VERSION 5.7 ;
  NOWIREEXTENSIONATPIN ON ;
  DIVIDERCHAR "/" ;
  BUSBITCHARS "[]" ;
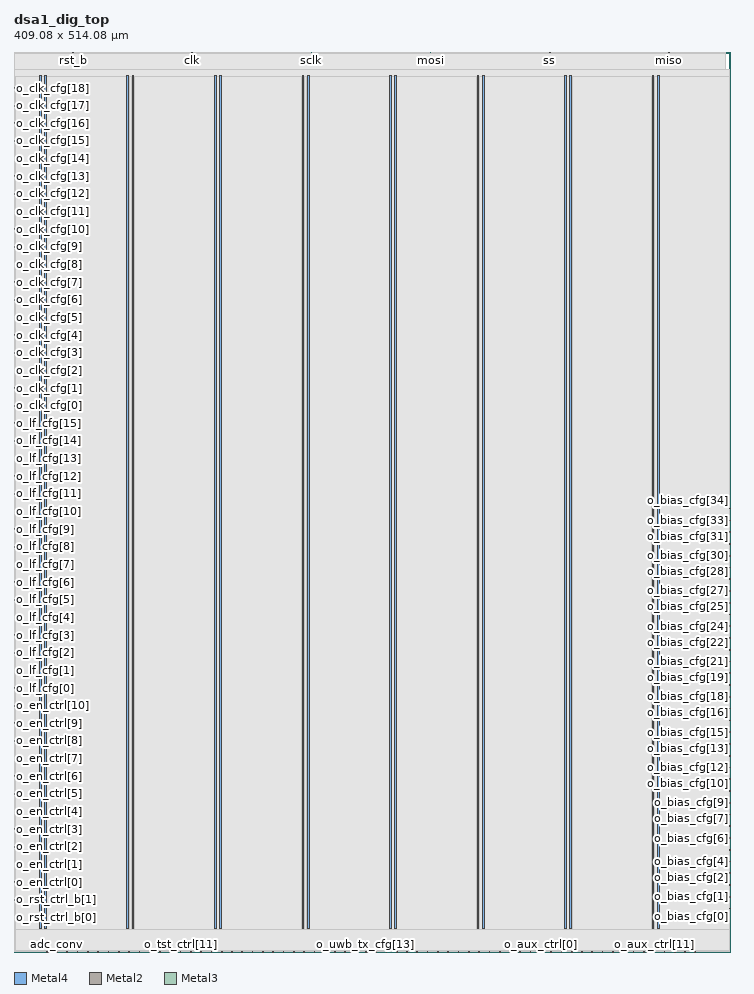
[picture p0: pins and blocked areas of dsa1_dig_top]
MACRO dsa1_dig_top
  CLASS BLOCK ;
  FOREIGN dsa1_dig_top ;
  ORIGIN 0.000 0.000 ;
  SIZE 409.080 BY 514.080 ;
  PIN VDD
    DIRECTION INOUT ;
    USE POWER ;
    PORT
      LAYER Metal4 ;
        RECT 14.540 13.280 15.540 500.800 ;
    END
    PORT
      LAYER Metal4 ;
        RECT 64.540 13.280 65.540 500.800 ;
    END
    PORT
      LAYER Metal4 ;
        RECT 114.540 13.280 115.540 500.800 ;
    END
    PORT
      LAYER Metal4 ;
        RECT 164.540 13.280 165.540 500.800 ;
    END
    PORT
      LAYER Metal4 ;
        RECT 214.540 13.280 215.540 500.800 ;
    END
    PORT
      LAYER Metal4 ;
        RECT 264.540 13.280 265.540 500.800 ;
    END
    PORT
      LAYER Metal4 ;
        RECT 314.540 13.280 315.540 500.800 ;
    END
    PORT
      LAYER Metal4 ;
        RECT 364.540 13.280 365.540 500.800 ;
    END
  END VDD
  PIN VSS
    DIRECTION INOUT ;
    USE GROUND ;
    PORT
      LAYER Metal4 ;
        RECT 17.540 13.280 18.540 500.800 ;
    END
    PORT
      LAYER Metal4 ;
        RECT 67.540 13.280 68.540 500.800 ;
    END
    PORT
      LAYER Metal4 ;
        RECT 117.540 13.280 118.540 500.800 ;
    END
    PORT
      LAYER Metal4 ;
        RECT 167.540 13.280 168.540 500.800 ;
    END
    PORT
      LAYER Metal4 ;
        RECT 217.540 13.280 218.540 500.800 ;
    END
    PORT
      LAYER Metal4 ;
        RECT 267.540 13.280 268.540 500.800 ;
    END
    PORT
      LAYER Metal4 ;
        RECT 317.540 13.280 318.540 500.800 ;
    END
    PORT
      LAYER Metal4 ;
        RECT 367.540 13.280 368.540 500.800 ;
    END
  END VSS
  PIN adc_conv
    DIRECTION OUTPUT ;
    USE SIGNAL ;
    ANTENNADIFFAREA 0.741200 ;
    PORT
      LAYER Metal2 ;
        RECT 24.370 0.000 24.770 0.400 ;
    END
  END adc_conv
  PIN clk
    DIRECTION INPUT ;
    USE SIGNAL ;
    ANTENNAGATEAREA 0.566800 ;
    PORT
      LAYER Metal2 ;
        RECT 101.650 513.680 102.050 514.080 ;
    END
  END clk
  PIN data_in
    DIRECTION INPUT ;
    USE SIGNAL ;
    ANTENNAGATEAREA 0.101400 ;
    PORT
      LAYER Metal2 ;
        RECT 18.490 0.000 18.890 0.400 ;
    END
  END data_in
  PIN miso
    DIRECTION OUTPUT ;
    USE SIGNAL ;
    ANTENNADIFFAREA 0.741200 ;
    PORT
      LAYER Metal2 ;
        RECT 373.810 513.680 374.210 514.080 ;
    END
  END miso
  PIN mosi
    DIRECTION INPUT ;
    USE SIGNAL ;
    ANTENNAGATEAREA 0.101400 ;
    PORT
      LAYER Metal2 ;
        RECT 237.730 513.680 238.130 514.080 ;
    END
  END mosi
  PIN o_aux_ctrl[0]
    DIRECTION OUTPUT ;
    USE SIGNAL ;
    ANTENNADIFFAREA 0.741200 ;
    PORT
      LAYER Metal2 ;
        RECT 300.730 0.000 301.130 0.400 ;
    END
  END o_aux_ctrl[0]
  PIN o_aux_ctrl[10]
    DIRECTION OUTPUT ;
    USE SIGNAL ;
    ANTENNADIFFAREA 0.741200 ;
    PORT
      LAYER Metal2 ;
        RECT 359.530 0.000 359.930 0.400 ;
    END
  END o_aux_ctrl[10]
  PIN o_aux_ctrl[11]
    DIRECTION OUTPUT ;
    USE SIGNAL ;
    ANTENNADIFFAREA 0.741200 ;
    PORT
      LAYER Metal2 ;
        RECT 365.410 0.000 365.810 0.400 ;
    END
  END o_aux_ctrl[11]
  PIN o_aux_ctrl[12]
    DIRECTION OUTPUT ;
    USE SIGNAL ;
    ANTENNADIFFAREA 0.741200 ;
    PORT
      LAYER Metal2 ;
        RECT 371.290 0.000 371.690 0.400 ;
    END
  END o_aux_ctrl[12]
  PIN o_aux_ctrl[13]
    DIRECTION OUTPUT ;
    USE SIGNAL ;
    ANTENNADIFFAREA 0.741200 ;
    PORT
      LAYER Metal2 ;
        RECT 377.170 0.000 377.570 0.400 ;
    END
  END o_aux_ctrl[13]
  PIN o_aux_ctrl[14]
    DIRECTION OUTPUT ;
    USE SIGNAL ;
    ANTENNADIFFAREA 0.741200 ;
    PORT
      LAYER Metal2 ;
        RECT 383.050 0.000 383.450 0.400 ;
    END
  END o_aux_ctrl[14]
  PIN o_aux_ctrl[15]
    DIRECTION OUTPUT ;
    USE SIGNAL ;
    ANTENNADIFFAREA 0.741200 ;
    PORT
      LAYER Metal2 ;
        RECT 388.930 0.000 389.330 0.400 ;
    END
  END o_aux_ctrl[15]
  PIN o_aux_ctrl[1]
    DIRECTION OUTPUT ;
    USE SIGNAL ;
    ANTENNADIFFAREA 0.741200 ;
    PORT
      LAYER Metal2 ;
        RECT 306.610 0.000 307.010 0.400 ;
    END
  END o_aux_ctrl[1]
  PIN o_aux_ctrl[2]
    DIRECTION OUTPUT ;
    USE SIGNAL ;
    ANTENNADIFFAREA 0.741200 ;
    PORT
      LAYER Metal2 ;
        RECT 312.490 0.000 312.890 0.400 ;
    END
  END o_aux_ctrl[2]
  PIN o_aux_ctrl[3]
    DIRECTION OUTPUT ;
    USE SIGNAL ;
    ANTENNADIFFAREA 0.741200 ;
    PORT
      LAYER Metal2 ;
        RECT 318.370 0.000 318.770 0.400 ;
    END
  END o_aux_ctrl[3]
  PIN o_aux_ctrl[4]
    DIRECTION OUTPUT ;
    USE SIGNAL ;
    ANTENNADIFFAREA 0.741200 ;
    PORT
      LAYER Metal2 ;
        RECT 324.250 0.000 324.650 0.400 ;
    END
  END o_aux_ctrl[4]
  PIN o_aux_ctrl[5]
    DIRECTION OUTPUT ;
    USE SIGNAL ;
    ANTENNADIFFAREA 0.741200 ;
    PORT
      LAYER Metal2 ;
        RECT 330.130 0.000 330.530 0.400 ;
    END
  END o_aux_ctrl[5]
  PIN o_aux_ctrl[6]
    DIRECTION OUTPUT ;
    USE SIGNAL ;
    ANTENNADIFFAREA 0.741200 ;
    PORT
      LAYER Metal2 ;
        RECT 336.010 0.000 336.410 0.400 ;
    END
  END o_aux_ctrl[6]
  PIN o_aux_ctrl[7]
    DIRECTION OUTPUT ;
    USE SIGNAL ;
    ANTENNADIFFAREA 0.741200 ;
    PORT
      LAYER Metal2 ;
        RECT 341.890 0.000 342.290 0.400 ;
    END
  END o_aux_ctrl[7]
  PIN o_aux_ctrl[8]
    DIRECTION OUTPUT ;
    USE SIGNAL ;
    ANTENNADIFFAREA 0.741200 ;
    PORT
      LAYER Metal2 ;
        RECT 347.770 0.000 348.170 0.400 ;
    END
  END o_aux_ctrl[8]
  PIN o_aux_ctrl[9]
    DIRECTION OUTPUT ;
    USE SIGNAL ;
    ANTENNADIFFAREA 0.741200 ;
    PORT
      LAYER Metal2 ;
        RECT 353.650 0.000 354.050 0.400 ;
    END
  END o_aux_ctrl[9]
  PIN o_bias_cfg[0]
    DIRECTION OUTPUT ;
    USE SIGNAL ;
    ANTENNADIFFAREA 0.741200 ;
    PORT
      LAYER Metal3 ;
        RECT 408.680 24.580 409.080 24.980 ;
    END
  END o_bias_cfg[0]
  PIN o_bias_cfg[10]
    DIRECTION OUTPUT ;
    USE SIGNAL ;
    ANTENNADIFFAREA 0.741200 ;
    PORT
      LAYER Metal3 ;
        RECT 408.680 91.780 409.080 92.180 ;
    END
  END o_bias_cfg[10]
  PIN o_bias_cfg[11]
    DIRECTION OUTPUT ;
    USE SIGNAL ;
    ANTENNADIFFAREA 0.741200 ;
    PORT
      LAYER Metal3 ;
        RECT 408.680 98.500 409.080 98.900 ;
    END
  END o_bias_cfg[11]
  PIN o_bias_cfg[12]
    DIRECTION OUTPUT ;
    USE SIGNAL ;
    ANTENNADIFFAREA 0.741200 ;
    PORT
      LAYER Metal3 ;
        RECT 408.680 105.220 409.080 105.620 ;
    END
  END o_bias_cfg[12]
  PIN o_bias_cfg[13]
    DIRECTION OUTPUT ;
    USE SIGNAL ;
    ANTENNADIFFAREA 0.741200 ;
    PORT
      LAYER Metal3 ;
        RECT 408.680 111.940 409.080 112.340 ;
    END
  END o_bias_cfg[13]
  PIN o_bias_cfg[14]
    DIRECTION OUTPUT ;
    USE SIGNAL ;
    ANTENNADIFFAREA 0.741200 ;
    PORT
      LAYER Metal3 ;
        RECT 408.680 118.660 409.080 119.060 ;
    END
  END o_bias_cfg[14]
  PIN o_bias_cfg[15]
    DIRECTION OUTPUT ;
    USE SIGNAL ;
    ANTENNADIFFAREA 0.741200 ;
    PORT
      LAYER Metal3 ;
        RECT 408.680 125.380 409.080 125.780 ;
    END
  END o_bias_cfg[15]
  PIN o_bias_cfg[16]
    DIRECTION OUTPUT ;
    USE SIGNAL ;
    ANTENNADIFFAREA 0.741200 ;
    PORT
      LAYER Metal3 ;
        RECT 408.680 132.100 409.080 132.500 ;
    END
  END o_bias_cfg[16]
  PIN o_bias_cfg[17]
    DIRECTION OUTPUT ;
    USE SIGNAL ;
    ANTENNADIFFAREA 0.741200 ;
    PORT
      LAYER Metal3 ;
        RECT 408.680 138.820 409.080 139.220 ;
    END
  END o_bias_cfg[17]
  PIN o_bias_cfg[18]
    DIRECTION OUTPUT ;
    USE SIGNAL ;
    ANTENNADIFFAREA 0.741200 ;
    PORT
      LAYER Metal3 ;
        RECT 408.680 145.540 409.080 145.940 ;
    END
  END o_bias_cfg[18]
  PIN o_bias_cfg[19]
    DIRECTION OUTPUT ;
    USE SIGNAL ;
    ANTENNADIFFAREA 0.741200 ;
    PORT
      LAYER Metal3 ;
        RECT 408.680 152.260 409.080 152.660 ;
    END
  END o_bias_cfg[19]
  PIN o_bias_cfg[1]
    DIRECTION OUTPUT ;
    USE SIGNAL ;
    ANTENNADIFFAREA 0.741200 ;
    PORT
      LAYER Metal3 ;
        RECT 408.680 31.300 409.080 31.700 ;
    END
  END o_bias_cfg[1]
  PIN o_bias_cfg[20]
    DIRECTION OUTPUT ;
    USE SIGNAL ;
    ANTENNADIFFAREA 0.741200 ;
    PORT
      LAYER Metal3 ;
        RECT 408.680 158.980 409.080 159.380 ;
    END
  END o_bias_cfg[20]
  PIN o_bias_cfg[21]
    DIRECTION OUTPUT ;
    USE SIGNAL ;
    ANTENNADIFFAREA 0.741200 ;
    PORT
      LAYER Metal3 ;
        RECT 408.680 165.700 409.080 166.100 ;
    END
  END o_bias_cfg[21]
  PIN o_bias_cfg[22]
    DIRECTION OUTPUT ;
    USE SIGNAL ;
    ANTENNADIFFAREA 0.741200 ;
    PORT
      LAYER Metal3 ;
        RECT 408.680 172.420 409.080 172.820 ;
    END
  END o_bias_cfg[22]
  PIN o_bias_cfg[23]
    DIRECTION OUTPUT ;
    USE SIGNAL ;
    ANTENNADIFFAREA 0.741200 ;
    PORT
      LAYER Metal3 ;
        RECT 408.680 179.140 409.080 179.540 ;
    END
  END o_bias_cfg[23]
  PIN o_bias_cfg[24]
    DIRECTION OUTPUT ;
    USE SIGNAL ;
    ANTENNADIFFAREA 0.741200 ;
    PORT
      LAYER Metal3 ;
        RECT 408.680 185.860 409.080 186.260 ;
    END
  END o_bias_cfg[24]
  PIN o_bias_cfg[25]
    DIRECTION OUTPUT ;
    USE SIGNAL ;
    ANTENNADIFFAREA 0.741200 ;
    PORT
      LAYER Metal3 ;
        RECT 408.680 192.580 409.080 192.980 ;
    END
  END o_bias_cfg[25]
  PIN o_bias_cfg[26]
    DIRECTION OUTPUT ;
    USE SIGNAL ;
    ANTENNADIFFAREA 0.741200 ;
    PORT
      LAYER Metal3 ;
        RECT 408.680 199.300 409.080 199.700 ;
    END
  END o_bias_cfg[26]
  PIN o_bias_cfg[27]
    DIRECTION OUTPUT ;
    USE SIGNAL ;
    ANTENNADIFFAREA 0.741200 ;
    PORT
      LAYER Metal3 ;
        RECT 408.680 206.020 409.080 206.420 ;
    END
  END o_bias_cfg[27]
  PIN o_bias_cfg[28]
    DIRECTION OUTPUT ;
    USE SIGNAL ;
    ANTENNADIFFAREA 0.741200 ;
    PORT
      LAYER Metal3 ;
        RECT 408.680 212.740 409.080 213.140 ;
    END
  END o_bias_cfg[28]
  PIN o_bias_cfg[29]
    DIRECTION OUTPUT ;
    USE SIGNAL ;
    ANTENNADIFFAREA 0.741200 ;
    PORT
      LAYER Metal3 ;
        RECT 408.680 219.460 409.080 219.860 ;
    END
  END o_bias_cfg[29]
  PIN o_bias_cfg[2]
    DIRECTION OUTPUT ;
    USE SIGNAL ;
    ANTENNADIFFAREA 0.741200 ;
    PORT
      LAYER Metal3 ;
        RECT 408.680 38.020 409.080 38.420 ;
    END
  END o_bias_cfg[2]
  PIN o_bias_cfg[30]
    DIRECTION OUTPUT ;
    USE SIGNAL ;
    ANTENNADIFFAREA 0.741200 ;
    PORT
      LAYER Metal3 ;
        RECT 408.680 226.180 409.080 226.580 ;
    END
  END o_bias_cfg[30]
  PIN o_bias_cfg[31]
    DIRECTION OUTPUT ;
    USE SIGNAL ;
    ANTENNADIFFAREA 0.741200 ;
    PORT
      LAYER Metal3 ;
        RECT 408.680 232.900 409.080 233.300 ;
    END
  END o_bias_cfg[31]
  PIN o_bias_cfg[32]
    DIRECTION OUTPUT ;
    USE SIGNAL ;
    ANTENNADIFFAREA 0.741200 ;
    PORT
      LAYER Metal3 ;
        RECT 408.680 239.620 409.080 240.020 ;
    END
  END o_bias_cfg[32]
  PIN o_bias_cfg[33]
    DIRECTION OUTPUT ;
    USE SIGNAL ;
    ANTENNADIFFAREA 0.741200 ;
    PORT
      LAYER Metal3 ;
        RECT 408.680 246.340 409.080 246.740 ;
    END
  END o_bias_cfg[33]
  PIN o_bias_cfg[34]
    DIRECTION OUTPUT ;
    USE SIGNAL ;
    ANTENNADIFFAREA 0.741200 ;
    PORT
      LAYER Metal3 ;
        RECT 408.680 253.060 409.080 253.460 ;
    END
  END o_bias_cfg[34]
  PIN o_bias_cfg[3]
    DIRECTION OUTPUT ;
    USE SIGNAL ;
    ANTENNADIFFAREA 0.741200 ;
    PORT
      LAYER Metal3 ;
        RECT 408.680 44.740 409.080 45.140 ;
    END
  END o_bias_cfg[3]
  PIN o_bias_cfg[4]
    DIRECTION OUTPUT ;
    USE SIGNAL ;
    ANTENNADIFFAREA 0.741200 ;
    PORT
      LAYER Metal3 ;
        RECT 408.680 51.460 409.080 51.860 ;
    END
  END o_bias_cfg[4]
  PIN o_bias_cfg[5]
    DIRECTION OUTPUT ;
    USE SIGNAL ;
    ANTENNADIFFAREA 0.741200 ;
    PORT
      LAYER Metal3 ;
        RECT 408.680 58.180 409.080 58.580 ;
    END
  END o_bias_cfg[5]
  PIN o_bias_cfg[6]
    DIRECTION OUTPUT ;
    USE SIGNAL ;
    ANTENNADIFFAREA 0.741200 ;
    PORT
      LAYER Metal3 ;
        RECT 408.680 64.900 409.080 65.300 ;
    END
  END o_bias_cfg[6]
  PIN o_bias_cfg[7]
    DIRECTION OUTPUT ;
    USE SIGNAL ;
    ANTENNADIFFAREA 0.741200 ;
    PORT
      LAYER Metal3 ;
        RECT 408.680 71.620 409.080 72.020 ;
    END
  END o_bias_cfg[7]
  PIN o_bias_cfg[8]
    DIRECTION OUTPUT ;
    USE SIGNAL ;
    ANTENNADIFFAREA 0.741200 ;
    PORT
      LAYER Metal3 ;
        RECT 408.680 78.340 409.080 78.740 ;
    END
  END o_bias_cfg[8]
  PIN o_bias_cfg[9]
    DIRECTION OUTPUT ;
    USE SIGNAL ;
    ANTENNADIFFAREA 0.741200 ;
    PORT
      LAYER Metal3 ;
        RECT 408.680 85.060 409.080 85.460 ;
    END
  END o_bias_cfg[9]
  PIN o_clk_cfg[0]
    DIRECTION OUTPUT ;
    USE SIGNAL ;
    ANTENNADIFFAREA 0.741200 ;
    PORT
      LAYER Metal3 ;
        RECT 0.000 311.860 0.400 312.260 ;
    END
  END o_clk_cfg[0]
  PIN o_clk_cfg[10]
    DIRECTION OUTPUT ;
    USE SIGNAL ;
    ANTENNADIFFAREA 0.741200 ;
    PORT
      LAYER Metal3 ;
        RECT 0.000 412.660 0.400 413.060 ;
    END
  END o_clk_cfg[10]
  PIN o_clk_cfg[11]
    DIRECTION OUTPUT ;
    USE SIGNAL ;
    ANTENNADIFFAREA 0.741200 ;
    PORT
      LAYER Metal3 ;
        RECT 0.000 422.740 0.400 423.140 ;
    END
  END o_clk_cfg[11]
  PIN o_clk_cfg[12]
    DIRECTION OUTPUT ;
    USE SIGNAL ;
    ANTENNADIFFAREA 0.741200 ;
    PORT
      LAYER Metal3 ;
        RECT 0.000 432.820 0.400 433.220 ;
    END
  END o_clk_cfg[12]
  PIN o_clk_cfg[13]
    DIRECTION OUTPUT ;
    USE SIGNAL ;
    ANTENNADIFFAREA 0.741200 ;
    PORT
      LAYER Metal3 ;
        RECT 0.000 442.900 0.400 443.300 ;
    END
  END o_clk_cfg[13]
  PIN o_clk_cfg[14]
    DIRECTION OUTPUT ;
    USE SIGNAL ;
    ANTENNADIFFAREA 0.741200 ;
    PORT
      LAYER Metal3 ;
        RECT 0.000 452.980 0.400 453.380 ;
    END
  END o_clk_cfg[14]
  PIN o_clk_cfg[15]
    DIRECTION OUTPUT ;
    USE SIGNAL ;
    ANTENNADIFFAREA 0.741200 ;
    PORT
      LAYER Metal3 ;
        RECT 0.000 463.060 0.400 463.460 ;
    END
  END o_clk_cfg[15]
  PIN o_clk_cfg[16]
    DIRECTION OUTPUT ;
    USE SIGNAL ;
    ANTENNADIFFAREA 0.741200 ;
    PORT
      LAYER Metal3 ;
        RECT 0.000 473.140 0.400 473.540 ;
    END
  END o_clk_cfg[16]
  PIN o_clk_cfg[17]
    DIRECTION OUTPUT ;
    USE SIGNAL ;
    ANTENNADIFFAREA 0.741200 ;
    PORT
      LAYER Metal3 ;
        RECT 0.000 483.220 0.400 483.620 ;
    END
  END o_clk_cfg[17]
  PIN o_clk_cfg[18]
    DIRECTION OUTPUT ;
    USE SIGNAL ;
    ANTENNADIFFAREA 0.741200 ;
    PORT
      LAYER Metal3 ;
        RECT 0.000 493.300 0.400 493.700 ;
    END
  END o_clk_cfg[18]
  PIN o_clk_cfg[1]
    DIRECTION OUTPUT ;
    USE SIGNAL ;
    ANTENNADIFFAREA 0.741200 ;
    PORT
      LAYER Metal3 ;
        RECT 0.000 321.940 0.400 322.340 ;
    END
  END o_clk_cfg[1]
  PIN o_clk_cfg[2]
    DIRECTION OUTPUT ;
    USE SIGNAL ;
    ANTENNADIFFAREA 0.741200 ;
    PORT
      LAYER Metal3 ;
        RECT 0.000 332.020 0.400 332.420 ;
    END
  END o_clk_cfg[2]
  PIN o_clk_cfg[3]
    DIRECTION OUTPUT ;
    USE SIGNAL ;
    ANTENNADIFFAREA 0.741200 ;
    PORT
      LAYER Metal3 ;
        RECT 0.000 342.100 0.400 342.500 ;
    END
  END o_clk_cfg[3]
  PIN o_clk_cfg[4]
    DIRECTION OUTPUT ;
    USE SIGNAL ;
    ANTENNADIFFAREA 0.741200 ;
    PORT
      LAYER Metal3 ;
        RECT 0.000 352.180 0.400 352.580 ;
    END
  END o_clk_cfg[4]
  PIN o_clk_cfg[5]
    DIRECTION OUTPUT ;
    USE SIGNAL ;
    ANTENNADIFFAREA 0.741200 ;
    PORT
      LAYER Metal3 ;
        RECT 0.000 362.260 0.400 362.660 ;
    END
  END o_clk_cfg[5]
  PIN o_clk_cfg[6]
    DIRECTION OUTPUT ;
    USE SIGNAL ;
    ANTENNADIFFAREA 0.741200 ;
    PORT
      LAYER Metal3 ;
        RECT 0.000 372.340 0.400 372.740 ;
    END
  END o_clk_cfg[6]
  PIN o_clk_cfg[7]
    DIRECTION OUTPUT ;
    USE SIGNAL ;
    ANTENNADIFFAREA 0.741200 ;
    PORT
      LAYER Metal3 ;
        RECT 0.000 382.420 0.400 382.820 ;
    END
  END o_clk_cfg[7]
  PIN o_clk_cfg[8]
    DIRECTION OUTPUT ;
    USE SIGNAL ;
    ANTENNADIFFAREA 0.741200 ;
    PORT
      LAYER Metal3 ;
        RECT 0.000 392.500 0.400 392.900 ;
    END
  END o_clk_cfg[8]
  PIN o_clk_cfg[9]
    DIRECTION OUTPUT ;
    USE SIGNAL ;
    ANTENNADIFFAREA 0.741200 ;
    PORT
      LAYER Metal3 ;
        RECT 0.000 402.580 0.400 402.980 ;
    END
  END o_clk_cfg[9]
  PIN o_en_ctrl[0]
    DIRECTION OUTPUT ;
    USE SIGNAL ;
    ANTENNADIFFAREA 0.741200 ;
    PORT
      LAYER Metal3 ;
        RECT 0.000 39.700 0.400 40.100 ;
    END
  END o_en_ctrl[0]
  PIN o_en_ctrl[10]
    DIRECTION OUTPUT ;
    USE SIGNAL ;
    ANTENNADIFFAREA 0.741200 ;
    PORT
      LAYER Metal3 ;
        RECT 0.000 140.500 0.400 140.900 ;
    END
  END o_en_ctrl[10]
  PIN o_en_ctrl[1]
    DIRECTION OUTPUT ;
    USE SIGNAL ;
    ANTENNADIFFAREA 0.741200 ;
    PORT
      LAYER Metal3 ;
        RECT 0.000 49.780 0.400 50.180 ;
    END
  END o_en_ctrl[1]
  PIN o_en_ctrl[2]
    DIRECTION OUTPUT ;
    USE SIGNAL ;
    ANTENNADIFFAREA 0.741200 ;
    PORT
      LAYER Metal3 ;
        RECT 0.000 59.860 0.400 60.260 ;
    END
  END o_en_ctrl[2]
  PIN o_en_ctrl[3]
    DIRECTION OUTPUT ;
    USE SIGNAL ;
    ANTENNADIFFAREA 0.741200 ;
    PORT
      LAYER Metal3 ;
        RECT 0.000 69.940 0.400 70.340 ;
    END
  END o_en_ctrl[3]
  PIN o_en_ctrl[4]
    DIRECTION OUTPUT ;
    USE SIGNAL ;
    ANTENNADIFFAREA 0.741200 ;
    PORT
      LAYER Metal3 ;
        RECT 0.000 80.020 0.400 80.420 ;
    END
  END o_en_ctrl[4]
  PIN o_en_ctrl[5]
    DIRECTION OUTPUT ;
    USE SIGNAL ;
    ANTENNADIFFAREA 0.741200 ;
    PORT
      LAYER Metal3 ;
        RECT 0.000 90.100 0.400 90.500 ;
    END
  END o_en_ctrl[5]
  PIN o_en_ctrl[6]
    DIRECTION OUTPUT ;
    USE SIGNAL ;
    ANTENNADIFFAREA 0.741200 ;
    PORT
      LAYER Metal3 ;
        RECT 0.000 100.180 0.400 100.580 ;
    END
  END o_en_ctrl[6]
  PIN o_en_ctrl[7]
    DIRECTION OUTPUT ;
    USE SIGNAL ;
    ANTENNADIFFAREA 0.741200 ;
    PORT
      LAYER Metal3 ;
        RECT 0.000 110.260 0.400 110.660 ;
    END
  END o_en_ctrl[7]
  PIN o_en_ctrl[8]
    DIRECTION OUTPUT ;
    USE SIGNAL ;
    ANTENNADIFFAREA 0.741200 ;
    PORT
      LAYER Metal3 ;
        RECT 0.000 120.340 0.400 120.740 ;
    END
  END o_en_ctrl[8]
  PIN o_en_ctrl[9]
    DIRECTION OUTPUT ;
    USE SIGNAL ;
    ANTENNADIFFAREA 0.741200 ;
    PORT
      LAYER Metal3 ;
        RECT 0.000 130.420 0.400 130.820 ;
    END
  END o_en_ctrl[9]
  PIN o_lf_cfg[0]
    DIRECTION OUTPUT ;
    USE SIGNAL ;
    ANTENNADIFFAREA 0.741200 ;
    PORT
      LAYER Metal3 ;
        RECT 0.000 150.580 0.400 150.980 ;
    END
  END o_lf_cfg[0]
  PIN o_lf_cfg[10]
    DIRECTION OUTPUT ;
    USE SIGNAL ;
    ANTENNADIFFAREA 0.741200 ;
    PORT
      LAYER Metal3 ;
        RECT 0.000 251.380 0.400 251.780 ;
    END
  END o_lf_cfg[10]
  PIN o_lf_cfg[11]
    DIRECTION OUTPUT ;
    USE SIGNAL ;
    ANTENNADIFFAREA 0.741200 ;
    PORT
      LAYER Metal3 ;
        RECT 0.000 261.460 0.400 261.860 ;
    END
  END o_lf_cfg[11]
  PIN o_lf_cfg[12]
    DIRECTION OUTPUT ;
    USE SIGNAL ;
    ANTENNADIFFAREA 0.741200 ;
    PORT
      LAYER Metal3 ;
        RECT 0.000 271.540 0.400 271.940 ;
    END
  END o_lf_cfg[12]
  PIN o_lf_cfg[13]
    DIRECTION OUTPUT ;
    USE SIGNAL ;
    ANTENNADIFFAREA 0.741200 ;
    PORT
      LAYER Metal3 ;
        RECT 0.000 281.620 0.400 282.020 ;
    END
  END o_lf_cfg[13]
  PIN o_lf_cfg[14]
    DIRECTION OUTPUT ;
    USE SIGNAL ;
    ANTENNADIFFAREA 0.741200 ;
    PORT
      LAYER Metal3 ;
        RECT 0.000 291.700 0.400 292.100 ;
    END
  END o_lf_cfg[14]
  PIN o_lf_cfg[15]
    DIRECTION OUTPUT ;
    USE SIGNAL ;
    ANTENNADIFFAREA 0.741200 ;
    PORT
      LAYER Metal3 ;
        RECT 0.000 301.780 0.400 302.180 ;
    END
  END o_lf_cfg[15]
  PIN o_lf_cfg[1]
    DIRECTION OUTPUT ;
    USE SIGNAL ;
    ANTENNADIFFAREA 0.741200 ;
    PORT
      LAYER Metal3 ;
        RECT 0.000 160.660 0.400 161.060 ;
    END
  END o_lf_cfg[1]
  PIN o_lf_cfg[2]
    DIRECTION OUTPUT ;
    USE SIGNAL ;
    ANTENNADIFFAREA 0.741200 ;
    PORT
      LAYER Metal3 ;
        RECT 0.000 170.740 0.400 171.140 ;
    END
  END o_lf_cfg[2]
  PIN o_lf_cfg[3]
    DIRECTION OUTPUT ;
    USE SIGNAL ;
    ANTENNADIFFAREA 0.741200 ;
    PORT
      LAYER Metal3 ;
        RECT 0.000 180.820 0.400 181.220 ;
    END
  END o_lf_cfg[3]
  PIN o_lf_cfg[4]
    DIRECTION OUTPUT ;
    USE SIGNAL ;
    ANTENNADIFFAREA 0.741200 ;
    PORT
      LAYER Metal3 ;
        RECT 0.000 190.900 0.400 191.300 ;
    END
  END o_lf_cfg[4]
  PIN o_lf_cfg[5]
    DIRECTION OUTPUT ;
    USE SIGNAL ;
    ANTENNADIFFAREA 0.741200 ;
    PORT
      LAYER Metal3 ;
        RECT 0.000 200.980 0.400 201.380 ;
    END
  END o_lf_cfg[5]
  PIN o_lf_cfg[6]
    DIRECTION OUTPUT ;
    USE SIGNAL ;
    ANTENNADIFFAREA 0.741200 ;
    PORT
      LAYER Metal3 ;
        RECT 0.000 211.060 0.400 211.460 ;
    END
  END o_lf_cfg[6]
  PIN o_lf_cfg[7]
    DIRECTION OUTPUT ;
    USE SIGNAL ;
    ANTENNADIFFAREA 0.741200 ;
    PORT
      LAYER Metal3 ;
        RECT 0.000 221.140 0.400 221.540 ;
    END
  END o_lf_cfg[7]
  PIN o_lf_cfg[8]
    DIRECTION OUTPUT ;
    USE SIGNAL ;
    ANTENNADIFFAREA 0.741200 ;
    PORT
      LAYER Metal3 ;
        RECT 0.000 231.220 0.400 231.620 ;
    END
  END o_lf_cfg[8]
  PIN o_lf_cfg[9]
    DIRECTION OUTPUT ;
    USE SIGNAL ;
    ANTENNADIFFAREA 0.741200 ;
    PORT
      LAYER Metal3 ;
        RECT 0.000 241.300 0.400 241.700 ;
    END
  END o_lf_cfg[9]
  PIN o_rst_ctrl_b[0]
    DIRECTION OUTPUT ;
    USE SIGNAL ;
    ANTENNADIFFAREA 0.741200 ;
    PORT
      LAYER Metal3 ;
        RECT 0.000 19.540 0.400 19.940 ;
    END
  END o_rst_ctrl_b[0]
  PIN o_rst_ctrl_b[1]
    DIRECTION OUTPUT ;
    USE SIGNAL ;
    ANTENNADIFFAREA 0.741200 ;
    PORT
      LAYER Metal3 ;
        RECT 0.000 29.620 0.400 30.020 ;
    END
  END o_rst_ctrl_b[1]
  PIN o_tst_ctrl[0]
    DIRECTION OUTPUT ;
    USE SIGNAL ;
    ANTENNADIFFAREA 0.741200 ;
    PORT
      LAYER Metal2 ;
        RECT 30.250 0.000 30.650 0.400 ;
    END
  END o_tst_ctrl[0]
  PIN o_tst_ctrl[10]
    DIRECTION OUTPUT ;
    USE SIGNAL ;
    ANTENNADIFFAREA 0.741200 ;
    PORT
      LAYER Metal2 ;
        RECT 89.050 0.000 89.450 0.400 ;
    END
  END o_tst_ctrl[10]
  PIN o_tst_ctrl[11]
    DIRECTION OUTPUT ;
    USE SIGNAL ;
    ANTENNADIFFAREA 0.741200 ;
    PORT
      LAYER Metal2 ;
        RECT 94.930 0.000 95.330 0.400 ;
    END
  END o_tst_ctrl[11]
  PIN o_tst_ctrl[12]
    DIRECTION OUTPUT ;
    USE SIGNAL ;
    ANTENNADIFFAREA 0.741200 ;
    PORT
      LAYER Metal2 ;
        RECT 100.810 0.000 101.210 0.400 ;
    END
  END o_tst_ctrl[12]
  PIN o_tst_ctrl[13]
    DIRECTION OUTPUT ;
    USE SIGNAL ;
    ANTENNADIFFAREA 0.741200 ;
    PORT
      LAYER Metal2 ;
        RECT 106.690 0.000 107.090 0.400 ;
    END
  END o_tst_ctrl[13]
  PIN o_tst_ctrl[14]
    DIRECTION OUTPUT ;
    USE SIGNAL ;
    ANTENNADIFFAREA 0.741200 ;
    PORT
      LAYER Metal2 ;
        RECT 112.570 0.000 112.970 0.400 ;
    END
  END o_tst_ctrl[14]
  PIN o_tst_ctrl[15]
    DIRECTION OUTPUT ;
    USE SIGNAL ;
    ANTENNADIFFAREA 0.741200 ;
    PORT
      LAYER Metal2 ;
        RECT 118.450 0.000 118.850 0.400 ;
    END
  END o_tst_ctrl[15]
  PIN o_tst_ctrl[1]
    DIRECTION OUTPUT ;
    USE SIGNAL ;
    ANTENNADIFFAREA 0.741200 ;
    PORT
      LAYER Metal2 ;
        RECT 36.130 0.000 36.530 0.400 ;
    END
  END o_tst_ctrl[1]
  PIN o_tst_ctrl[2]
    DIRECTION OUTPUT ;
    USE SIGNAL ;
    ANTENNADIFFAREA 0.741200 ;
    PORT
      LAYER Metal2 ;
        RECT 42.010 0.000 42.410 0.400 ;
    END
  END o_tst_ctrl[2]
  PIN o_tst_ctrl[3]
    DIRECTION OUTPUT ;
    USE SIGNAL ;
    ANTENNADIFFAREA 0.741200 ;
    PORT
      LAYER Metal2 ;
        RECT 47.890 0.000 48.290 0.400 ;
    END
  END o_tst_ctrl[3]
  PIN o_tst_ctrl[4]
    DIRECTION OUTPUT ;
    USE SIGNAL ;
    ANTENNADIFFAREA 0.741200 ;
    PORT
      LAYER Metal2 ;
        RECT 53.770 0.000 54.170 0.400 ;
    END
  END o_tst_ctrl[4]
  PIN o_tst_ctrl[5]
    DIRECTION OUTPUT ;
    USE SIGNAL ;
    ANTENNADIFFAREA 0.741200 ;
    PORT
      LAYER Metal2 ;
        RECT 59.650 0.000 60.050 0.400 ;
    END
  END o_tst_ctrl[5]
  PIN o_tst_ctrl[6]
    DIRECTION OUTPUT ;
    USE SIGNAL ;
    ANTENNADIFFAREA 0.741200 ;
    PORT
      LAYER Metal2 ;
        RECT 65.530 0.000 65.930 0.400 ;
    END
  END o_tst_ctrl[6]
  PIN o_tst_ctrl[7]
    DIRECTION OUTPUT ;
    USE SIGNAL ;
    ANTENNADIFFAREA 0.741200 ;
    PORT
      LAYER Metal2 ;
        RECT 71.410 0.000 71.810 0.400 ;
    END
  END o_tst_ctrl[7]
  PIN o_tst_ctrl[8]
    DIRECTION OUTPUT ;
    USE SIGNAL ;
    ANTENNADIFFAREA 0.741200 ;
    PORT
      LAYER Metal2 ;
        RECT 77.290 0.000 77.690 0.400 ;
    END
  END o_tst_ctrl[8]
  PIN o_tst_ctrl[9]
    DIRECTION OUTPUT ;
    USE SIGNAL ;
    ANTENNADIFFAREA 0.741200 ;
    PORT
      LAYER Metal2 ;
        RECT 83.170 0.000 83.570 0.400 ;
    END
  END o_tst_ctrl[9]
  PIN o_uwb_tx_cfg[0]
    DIRECTION OUTPUT ;
    USE SIGNAL ;
    ANTENNADIFFAREA 0.741200 ;
    PORT
      LAYER Metal2 ;
        RECT 124.330 0.000 124.730 0.400 ;
    END
  END o_uwb_tx_cfg[0]
  PIN o_uwb_tx_cfg[10]
    DIRECTION OUTPUT ;
    USE SIGNAL ;
    ANTENNADIFFAREA 0.741200 ;
    PORT
      LAYER Metal2 ;
        RECT 183.130 0.000 183.530 0.400 ;
    END
  END o_uwb_tx_cfg[10]
  PIN o_uwb_tx_cfg[11]
    DIRECTION OUTPUT ;
    USE SIGNAL ;
    ANTENNADIFFAREA 0.741200 ;
    PORT
      LAYER Metal2 ;
        RECT 189.010 0.000 189.410 0.400 ;
    END
  END o_uwb_tx_cfg[11]
  PIN o_uwb_tx_cfg[12]
    DIRECTION OUTPUT ;
    USE SIGNAL ;
    ANTENNADIFFAREA 0.741200 ;
    PORT
      LAYER Metal2 ;
        RECT 194.890 0.000 195.290 0.400 ;
    END
  END o_uwb_tx_cfg[12]
  PIN o_uwb_tx_cfg[13]
    DIRECTION OUTPUT ;
    USE SIGNAL ;
    ANTENNADIFFAREA 0.741200 ;
    PORT
      LAYER Metal2 ;
        RECT 200.770 0.000 201.170 0.400 ;
    END
  END o_uwb_tx_cfg[13]
  PIN o_uwb_tx_cfg[14]
    DIRECTION OUTPUT ;
    USE SIGNAL ;
    ANTENNADIFFAREA 0.741200 ;
    PORT
      LAYER Metal2 ;
        RECT 206.650 0.000 207.050 0.400 ;
    END
  END o_uwb_tx_cfg[14]
  PIN o_uwb_tx_cfg[15]
    DIRECTION OUTPUT ;
    USE SIGNAL ;
    ANTENNADIFFAREA 0.741200 ;
    PORT
      LAYER Metal2 ;
        RECT 212.530 0.000 212.930 0.400 ;
    END
  END o_uwb_tx_cfg[15]
  PIN o_uwb_tx_cfg[16]
    DIRECTION OUTPUT ;
    USE SIGNAL ;
    ANTENNADIFFAREA 0.741200 ;
    PORT
      LAYER Metal2 ;
        RECT 218.410 0.000 218.810 0.400 ;
    END
  END o_uwb_tx_cfg[16]
  PIN o_uwb_tx_cfg[17]
    DIRECTION OUTPUT ;
    USE SIGNAL ;
    ANTENNADIFFAREA 0.741200 ;
    PORT
      LAYER Metal2 ;
        RECT 224.290 0.000 224.690 0.400 ;
    END
  END o_uwb_tx_cfg[17]
  PIN o_uwb_tx_cfg[18]
    DIRECTION OUTPUT ;
    USE SIGNAL ;
    ANTENNADIFFAREA 0.741200 ;
    PORT
      LAYER Metal2 ;
        RECT 230.170 0.000 230.570 0.400 ;
    END
  END o_uwb_tx_cfg[18]
  PIN o_uwb_tx_cfg[19]
    DIRECTION OUTPUT ;
    USE SIGNAL ;
    ANTENNADIFFAREA 0.741200 ;
    PORT
      LAYER Metal2 ;
        RECT 236.050 0.000 236.450 0.400 ;
    END
  END o_uwb_tx_cfg[19]
  PIN o_uwb_tx_cfg[1]
    DIRECTION OUTPUT ;
    USE SIGNAL ;
    ANTENNADIFFAREA 0.741200 ;
    PORT
      LAYER Metal2 ;
        RECT 130.210 0.000 130.610 0.400 ;
    END
  END o_uwb_tx_cfg[1]
  PIN o_uwb_tx_cfg[20]
    DIRECTION OUTPUT ;
    USE SIGNAL ;
    ANTENNADIFFAREA 0.741200 ;
    PORT
      LAYER Metal2 ;
        RECT 241.930 0.000 242.330 0.400 ;
    END
  END o_uwb_tx_cfg[20]
  PIN o_uwb_tx_cfg[21]
    DIRECTION OUTPUT ;
    USE SIGNAL ;
    ANTENNADIFFAREA 0.741200 ;
    PORT
      LAYER Metal2 ;
        RECT 247.810 0.000 248.210 0.400 ;
    END
  END o_uwb_tx_cfg[21]
  PIN o_uwb_tx_cfg[22]
    DIRECTION OUTPUT ;
    USE SIGNAL ;
    ANTENNADIFFAREA 0.741200 ;
    PORT
      LAYER Metal2 ;
        RECT 253.690 0.000 254.090 0.400 ;
    END
  END o_uwb_tx_cfg[22]
  PIN o_uwb_tx_cfg[23]
    DIRECTION OUTPUT ;
    USE SIGNAL ;
    ANTENNADIFFAREA 0.741200 ;
    PORT
      LAYER Metal2 ;
        RECT 259.570 0.000 259.970 0.400 ;
    END
  END o_uwb_tx_cfg[23]
  PIN o_uwb_tx_cfg[24]
    DIRECTION OUTPUT ;
    USE SIGNAL ;
    ANTENNADIFFAREA 0.741200 ;
    PORT
      LAYER Metal2 ;
        RECT 265.450 0.000 265.850 0.400 ;
    END
  END o_uwb_tx_cfg[24]
  PIN o_uwb_tx_cfg[25]
    DIRECTION OUTPUT ;
    USE SIGNAL ;
    ANTENNADIFFAREA 0.741200 ;
    PORT
      LAYER Metal2 ;
        RECT 271.330 0.000 271.730 0.400 ;
    END
  END o_uwb_tx_cfg[25]
  PIN o_uwb_tx_cfg[26]
    DIRECTION OUTPUT ;
    USE SIGNAL ;
    ANTENNADIFFAREA 0.741200 ;
    PORT
      LAYER Metal2 ;
        RECT 277.210 0.000 277.610 0.400 ;
    END
  END o_uwb_tx_cfg[26]
  PIN o_uwb_tx_cfg[27]
    DIRECTION OUTPUT ;
    USE SIGNAL ;
    ANTENNADIFFAREA 0.741200 ;
    PORT
      LAYER Metal2 ;
        RECT 283.090 0.000 283.490 0.400 ;
    END
  END o_uwb_tx_cfg[27]
  PIN o_uwb_tx_cfg[28]
    DIRECTION OUTPUT ;
    USE SIGNAL ;
    ANTENNADIFFAREA 0.741200 ;
    PORT
      LAYER Metal2 ;
        RECT 288.970 0.000 289.370 0.400 ;
    END
  END o_uwb_tx_cfg[28]
  PIN o_uwb_tx_cfg[29]
    DIRECTION OUTPUT ;
    USE SIGNAL ;
    ANTENNADIFFAREA 0.741200 ;
    PORT
      LAYER Metal2 ;
        RECT 294.850 0.000 295.250 0.400 ;
    END
  END o_uwb_tx_cfg[29]
  PIN o_uwb_tx_cfg[2]
    DIRECTION OUTPUT ;
    USE SIGNAL ;
    ANTENNADIFFAREA 0.741200 ;
    PORT
      LAYER Metal2 ;
        RECT 136.090 0.000 136.490 0.400 ;
    END
  END o_uwb_tx_cfg[2]
  PIN o_uwb_tx_cfg[3]
    DIRECTION OUTPUT ;
    USE SIGNAL ;
    ANTENNADIFFAREA 0.741200 ;
    PORT
      LAYER Metal2 ;
        RECT 141.970 0.000 142.370 0.400 ;
    END
  END o_uwb_tx_cfg[3]
  PIN o_uwb_tx_cfg[4]
    DIRECTION OUTPUT ;
    USE SIGNAL ;
    ANTENNADIFFAREA 0.741200 ;
    PORT
      LAYER Metal2 ;
        RECT 147.850 0.000 148.250 0.400 ;
    END
  END o_uwb_tx_cfg[4]
  PIN o_uwb_tx_cfg[5]
    DIRECTION OUTPUT ;
    USE SIGNAL ;
    ANTENNADIFFAREA 0.741200 ;
    PORT
      LAYER Metal2 ;
        RECT 153.730 0.000 154.130 0.400 ;
    END
  END o_uwb_tx_cfg[5]
  PIN o_uwb_tx_cfg[6]
    DIRECTION OUTPUT ;
    USE SIGNAL ;
    ANTENNADIFFAREA 0.741200 ;
    PORT
      LAYER Metal2 ;
        RECT 159.610 0.000 160.010 0.400 ;
    END
  END o_uwb_tx_cfg[6]
  PIN o_uwb_tx_cfg[7]
    DIRECTION OUTPUT ;
    USE SIGNAL ;
    ANTENNADIFFAREA 0.741200 ;
    PORT
      LAYER Metal2 ;
        RECT 165.490 0.000 165.890 0.400 ;
    END
  END o_uwb_tx_cfg[7]
  PIN o_uwb_tx_cfg[8]
    DIRECTION OUTPUT ;
    USE SIGNAL ;
    ANTENNADIFFAREA 0.741200 ;
    PORT
      LAYER Metal2 ;
        RECT 171.370 0.000 171.770 0.400 ;
    END
  END o_uwb_tx_cfg[8]
  PIN o_uwb_tx_cfg[9]
    DIRECTION OUTPUT ;
    USE SIGNAL ;
    ANTENNADIFFAREA 0.741200 ;
    PORT
      LAYER Metal2 ;
        RECT 177.250 0.000 177.650 0.400 ;
    END
  END o_uwb_tx_cfg[9]
  PIN rst_b
    DIRECTION INPUT ;
    USE SIGNAL ;
    ANTENNAGATEAREA 0.101400 ;
    PORT
      LAYER Metal2 ;
        RECT 33.610 513.680 34.010 514.080 ;
    END
  END rst_b
  PIN sclk
    DIRECTION INPUT ;
    USE SIGNAL ;
    ANTENNAGATEAREA 0.566800 ;
    PORT
      LAYER Metal2 ;
        RECT 169.690 513.680 170.090 514.080 ;
    END
  END sclk
  PIN ss
    DIRECTION INPUT ;
    USE SIGNAL ;
    ANTENNAGATEAREA 0.101400 ;
    PORT
      LAYER Metal2 ;
        RECT 305.770 513.680 306.170 514.080 ;
    END
  END ss
  OBS
      LAYER GatPoly ;
        RECT 5.145 13.530 403.935 500.550 ;
      LAYER Metal1 ;
        RECT 5.040 13.280 404.040 500.800 ;
      LAYER Metal2 ;
        RECT 0.110 513.470 33.400 513.760 ;
        RECT 34.220 513.470 101.440 513.760 ;
        RECT 102.260 513.470 169.480 513.760 ;
        RECT 170.300 513.470 237.520 513.760 ;
        RECT 238.340 513.470 305.560 513.760 ;
        RECT 306.380 513.470 373.600 513.760 ;
        RECT 374.420 513.470 406.450 513.760 ;
        RECT 0.110 0.610 406.450 513.470 ;
        RECT 0.110 0.100 18.280 0.610 ;
        RECT 19.100 0.100 24.160 0.610 ;
        RECT 24.980 0.100 30.040 0.610 ;
        RECT 30.860 0.100 35.920 0.610 ;
        RECT 36.740 0.100 41.800 0.610 ;
        RECT 42.620 0.100 47.680 0.610 ;
        RECT 48.500 0.100 53.560 0.610 ;
        RECT 54.380 0.100 59.440 0.610 ;
        RECT 60.260 0.100 65.320 0.610 ;
        RECT 66.140 0.100 71.200 0.610 ;
        RECT 72.020 0.100 77.080 0.610 ;
        RECT 77.900 0.100 82.960 0.610 ;
        RECT 83.780 0.100 88.840 0.610 ;
        RECT 89.660 0.100 94.720 0.610 ;
        RECT 95.540 0.100 100.600 0.610 ;
        RECT 101.420 0.100 106.480 0.610 ;
        RECT 107.300 0.100 112.360 0.610 ;
        RECT 113.180 0.100 118.240 0.610 ;
        RECT 119.060 0.100 124.120 0.610 ;
        RECT 124.940 0.100 130.000 0.610 ;
        RECT 130.820 0.100 135.880 0.610 ;
        RECT 136.700 0.100 141.760 0.610 ;
        RECT 142.580 0.100 147.640 0.610 ;
        RECT 148.460 0.100 153.520 0.610 ;
        RECT 154.340 0.100 159.400 0.610 ;
        RECT 160.220 0.100 165.280 0.610 ;
        RECT 166.100 0.100 171.160 0.610 ;
        RECT 171.980 0.100 177.040 0.610 ;
        RECT 177.860 0.100 182.920 0.610 ;
        RECT 183.740 0.100 188.800 0.610 ;
        RECT 189.620 0.100 194.680 0.610 ;
        RECT 195.500 0.100 200.560 0.610 ;
        RECT 201.380 0.100 206.440 0.610 ;
        RECT 207.260 0.100 212.320 0.610 ;
        RECT 213.140 0.100 218.200 0.610 ;
        RECT 219.020 0.100 224.080 0.610 ;
        RECT 224.900 0.100 229.960 0.610 ;
        RECT 230.780 0.100 235.840 0.610 ;
        RECT 236.660 0.100 241.720 0.610 ;
        RECT 242.540 0.100 247.600 0.610 ;
        RECT 248.420 0.100 253.480 0.610 ;
        RECT 254.300 0.100 259.360 0.610 ;
        RECT 260.180 0.100 265.240 0.610 ;
        RECT 266.060 0.100 271.120 0.610 ;
        RECT 271.940 0.100 277.000 0.610 ;
        RECT 277.820 0.100 282.880 0.610 ;
        RECT 283.700 0.100 288.760 0.610 ;
        RECT 289.580 0.100 294.640 0.610 ;
        RECT 295.460 0.100 300.520 0.610 ;
        RECT 301.340 0.100 306.400 0.610 ;
        RECT 307.220 0.100 312.280 0.610 ;
        RECT 313.100 0.100 318.160 0.610 ;
        RECT 318.980 0.100 324.040 0.610 ;
        RECT 324.860 0.100 329.920 0.610 ;
        RECT 330.740 0.100 335.800 0.610 ;
        RECT 336.620 0.100 341.680 0.610 ;
        RECT 342.500 0.100 347.560 0.610 ;
        RECT 348.380 0.100 353.440 0.610 ;
        RECT 354.260 0.100 359.320 0.610 ;
        RECT 360.140 0.100 365.200 0.610 ;
        RECT 366.020 0.100 371.080 0.610 ;
        RECT 371.900 0.100 376.960 0.610 ;
        RECT 377.780 0.100 382.840 0.610 ;
        RECT 383.660 0.100 388.720 0.610 ;
        RECT 389.540 0.100 406.450 0.610 ;
      LAYER Metal3 ;
        RECT 0.065 493.910 408.680 504.100 ;
        RECT 0.610 493.090 408.680 493.910 ;
        RECT 0.065 483.830 408.680 493.090 ;
        RECT 0.610 483.010 408.680 483.830 ;
        RECT 0.065 473.750 408.680 483.010 ;
        RECT 0.610 472.930 408.680 473.750 ;
        RECT 0.065 463.670 408.680 472.930 ;
        RECT 0.610 462.850 408.680 463.670 ;
        RECT 0.065 453.590 408.680 462.850 ;
        RECT 0.610 452.770 408.680 453.590 ;
        RECT 0.065 443.510 408.680 452.770 ;
        RECT 0.610 442.690 408.680 443.510 ;
        RECT 0.065 433.430 408.680 442.690 ;
        RECT 0.610 432.610 408.680 433.430 ;
        RECT 0.065 423.350 408.680 432.610 ;
        RECT 0.610 422.530 408.680 423.350 ;
        RECT 0.065 413.270 408.680 422.530 ;
        RECT 0.610 412.450 408.680 413.270 ;
        RECT 0.065 403.190 408.680 412.450 ;
        RECT 0.610 402.370 408.680 403.190 ;
        RECT 0.065 393.110 408.680 402.370 ;
        RECT 0.610 392.290 408.680 393.110 ;
        RECT 0.065 383.030 408.680 392.290 ;
        RECT 0.610 382.210 408.680 383.030 ;
        RECT 0.065 372.950 408.680 382.210 ;
        RECT 0.610 372.130 408.680 372.950 ;
        RECT 0.065 362.870 408.680 372.130 ;
        RECT 0.610 362.050 408.680 362.870 ;
        RECT 0.065 352.790 408.680 362.050 ;
        RECT 0.610 351.970 408.680 352.790 ;
        RECT 0.065 342.710 408.680 351.970 ;
        RECT 0.610 341.890 408.680 342.710 ;
        RECT 0.065 332.630 408.680 341.890 ;
        RECT 0.610 331.810 408.680 332.630 ;
        RECT 0.065 322.550 408.680 331.810 ;
        RECT 0.610 321.730 408.680 322.550 ;
        RECT 0.065 312.470 408.680 321.730 ;
        RECT 0.610 311.650 408.680 312.470 ;
        RECT 0.065 302.390 408.680 311.650 ;
        RECT 0.610 301.570 408.680 302.390 ;
        RECT 0.065 292.310 408.680 301.570 ;
        RECT 0.610 291.490 408.680 292.310 ;
        RECT 0.065 282.230 408.680 291.490 ;
        RECT 0.610 281.410 408.680 282.230 ;
        RECT 0.065 272.150 408.680 281.410 ;
        RECT 0.610 271.330 408.680 272.150 ;
        RECT 0.065 262.070 408.680 271.330 ;
        RECT 0.610 261.250 408.680 262.070 ;
        RECT 0.065 253.670 408.680 261.250 ;
        RECT 0.065 252.850 408.470 253.670 ;
        RECT 0.065 251.990 408.680 252.850 ;
        RECT 0.610 251.170 408.680 251.990 ;
        RECT 0.065 246.950 408.680 251.170 ;
        RECT 0.065 246.130 408.470 246.950 ;
        RECT 0.065 241.910 408.680 246.130 ;
        RECT 0.610 241.090 408.680 241.910 ;
        RECT 0.065 240.230 408.680 241.090 ;
        RECT 0.065 239.410 408.470 240.230 ;
        RECT 0.065 233.510 408.680 239.410 ;
        RECT 0.065 232.690 408.470 233.510 ;
        RECT 0.065 231.830 408.680 232.690 ;
        RECT 0.610 231.010 408.680 231.830 ;
        RECT 0.065 226.790 408.680 231.010 ;
        RECT 0.065 225.970 408.470 226.790 ;
        RECT 0.065 221.750 408.680 225.970 ;
        RECT 0.610 220.930 408.680 221.750 ;
        RECT 0.065 220.070 408.680 220.930 ;
        RECT 0.065 219.250 408.470 220.070 ;
        RECT 0.065 213.350 408.680 219.250 ;
        RECT 0.065 212.530 408.470 213.350 ;
        RECT 0.065 211.670 408.680 212.530 ;
        RECT 0.610 210.850 408.680 211.670 ;
        RECT 0.065 206.630 408.680 210.850 ;
        RECT 0.065 205.810 408.470 206.630 ;
        RECT 0.065 201.590 408.680 205.810 ;
        RECT 0.610 200.770 408.680 201.590 ;
        RECT 0.065 199.910 408.680 200.770 ;
        RECT 0.065 199.090 408.470 199.910 ;
        RECT 0.065 193.190 408.680 199.090 ;
        RECT 0.065 192.370 408.470 193.190 ;
        RECT 0.065 191.510 408.680 192.370 ;
        RECT 0.610 190.690 408.680 191.510 ;
        RECT 0.065 186.470 408.680 190.690 ;
        RECT 0.065 185.650 408.470 186.470 ;
        RECT 0.065 181.430 408.680 185.650 ;
        RECT 0.610 180.610 408.680 181.430 ;
        RECT 0.065 179.750 408.680 180.610 ;
        RECT 0.065 178.930 408.470 179.750 ;
        RECT 0.065 173.030 408.680 178.930 ;
        RECT 0.065 172.210 408.470 173.030 ;
        RECT 0.065 171.350 408.680 172.210 ;
        RECT 0.610 170.530 408.680 171.350 ;
        RECT 0.065 166.310 408.680 170.530 ;
        RECT 0.065 165.490 408.470 166.310 ;
        RECT 0.065 161.270 408.680 165.490 ;
        RECT 0.610 160.450 408.680 161.270 ;
        RECT 0.065 159.590 408.680 160.450 ;
        RECT 0.065 158.770 408.470 159.590 ;
        RECT 0.065 152.870 408.680 158.770 ;
        RECT 0.065 152.050 408.470 152.870 ;
        RECT 0.065 151.190 408.680 152.050 ;
        RECT 0.610 150.370 408.680 151.190 ;
        RECT 0.065 146.150 408.680 150.370 ;
        RECT 0.065 145.330 408.470 146.150 ;
        RECT 0.065 141.110 408.680 145.330 ;
        RECT 0.610 140.290 408.680 141.110 ;
        RECT 0.065 139.430 408.680 140.290 ;
        RECT 0.065 138.610 408.470 139.430 ;
        RECT 0.065 132.710 408.680 138.610 ;
        RECT 0.065 131.890 408.470 132.710 ;
        RECT 0.065 131.030 408.680 131.890 ;
        RECT 0.610 130.210 408.680 131.030 ;
        RECT 0.065 125.990 408.680 130.210 ;
        RECT 0.065 125.170 408.470 125.990 ;
        RECT 0.065 120.950 408.680 125.170 ;
        RECT 0.610 120.130 408.680 120.950 ;
        RECT 0.065 119.270 408.680 120.130 ;
        RECT 0.065 118.450 408.470 119.270 ;
        RECT 0.065 112.550 408.680 118.450 ;
        RECT 0.065 111.730 408.470 112.550 ;
        RECT 0.065 110.870 408.680 111.730 ;
        RECT 0.610 110.050 408.680 110.870 ;
        RECT 0.065 105.830 408.680 110.050 ;
        RECT 0.065 105.010 408.470 105.830 ;
        RECT 0.065 100.790 408.680 105.010 ;
        RECT 0.610 99.970 408.680 100.790 ;
        RECT 0.065 99.110 408.680 99.970 ;
        RECT 0.065 98.290 408.470 99.110 ;
        RECT 0.065 92.390 408.680 98.290 ;
        RECT 0.065 91.570 408.470 92.390 ;
        RECT 0.065 90.710 408.680 91.570 ;
        RECT 0.610 89.890 408.680 90.710 ;
        RECT 0.065 85.670 408.680 89.890 ;
        RECT 0.065 84.850 408.470 85.670 ;
        RECT 0.065 80.630 408.680 84.850 ;
        RECT 0.610 79.810 408.680 80.630 ;
        RECT 0.065 78.950 408.680 79.810 ;
        RECT 0.065 78.130 408.470 78.950 ;
        RECT 0.065 72.230 408.680 78.130 ;
        RECT 0.065 71.410 408.470 72.230 ;
        RECT 0.065 70.550 408.680 71.410 ;
        RECT 0.610 69.730 408.680 70.550 ;
        RECT 0.065 65.510 408.680 69.730 ;
        RECT 0.065 64.690 408.470 65.510 ;
        RECT 0.065 60.470 408.680 64.690 ;
        RECT 0.610 59.650 408.680 60.470 ;
        RECT 0.065 58.790 408.680 59.650 ;
        RECT 0.065 57.970 408.470 58.790 ;
        RECT 0.065 52.070 408.680 57.970 ;
        RECT 0.065 51.250 408.470 52.070 ;
        RECT 0.065 50.390 408.680 51.250 ;
        RECT 0.610 49.570 408.680 50.390 ;
        RECT 0.065 45.350 408.680 49.570 ;
        RECT 0.065 44.530 408.470 45.350 ;
        RECT 0.065 40.310 408.680 44.530 ;
        RECT 0.610 39.490 408.680 40.310 ;
        RECT 0.065 38.630 408.680 39.490 ;
        RECT 0.065 37.810 408.470 38.630 ;
        RECT 0.065 31.910 408.680 37.810 ;
        RECT 0.065 31.090 408.470 31.910 ;
        RECT 0.065 30.230 408.680 31.090 ;
        RECT 0.610 29.410 408.680 30.230 ;
        RECT 0.065 25.190 408.680 29.410 ;
        RECT 0.065 24.370 408.470 25.190 ;
        RECT 0.065 20.150 408.680 24.370 ;
        RECT 0.610 19.330 408.680 20.150 ;
        RECT 0.065 0.320 408.680 19.330 ;
      LAYER Metal4 ;
        RECT 0.950 13.070 14.330 500.365 ;
        RECT 15.750 13.070 17.330 500.365 ;
        RECT 18.750 13.070 64.330 500.365 ;
        RECT 65.750 13.070 67.330 500.365 ;
        RECT 68.750 13.070 114.330 500.365 ;
        RECT 115.750 13.070 117.330 500.365 ;
        RECT 118.750 13.070 164.330 500.365 ;
        RECT 165.750 13.070 167.330 500.365 ;
        RECT 168.750 13.070 214.330 500.365 ;
        RECT 215.750 13.070 217.330 500.365 ;
        RECT 218.750 13.070 264.330 500.365 ;
        RECT 265.750 13.070 267.330 500.365 ;
        RECT 268.750 13.070 314.330 500.365 ;
        RECT 315.750 13.070 317.330 500.365 ;
        RECT 318.750 13.070 364.330 500.365 ;
        RECT 365.750 13.070 367.330 500.365 ;
        RECT 368.750 13.070 408.550 500.365 ;
        RECT 0.950 0.695 408.550 13.070 ;
  END
END dsa1_dig_top
END LIBRARY

